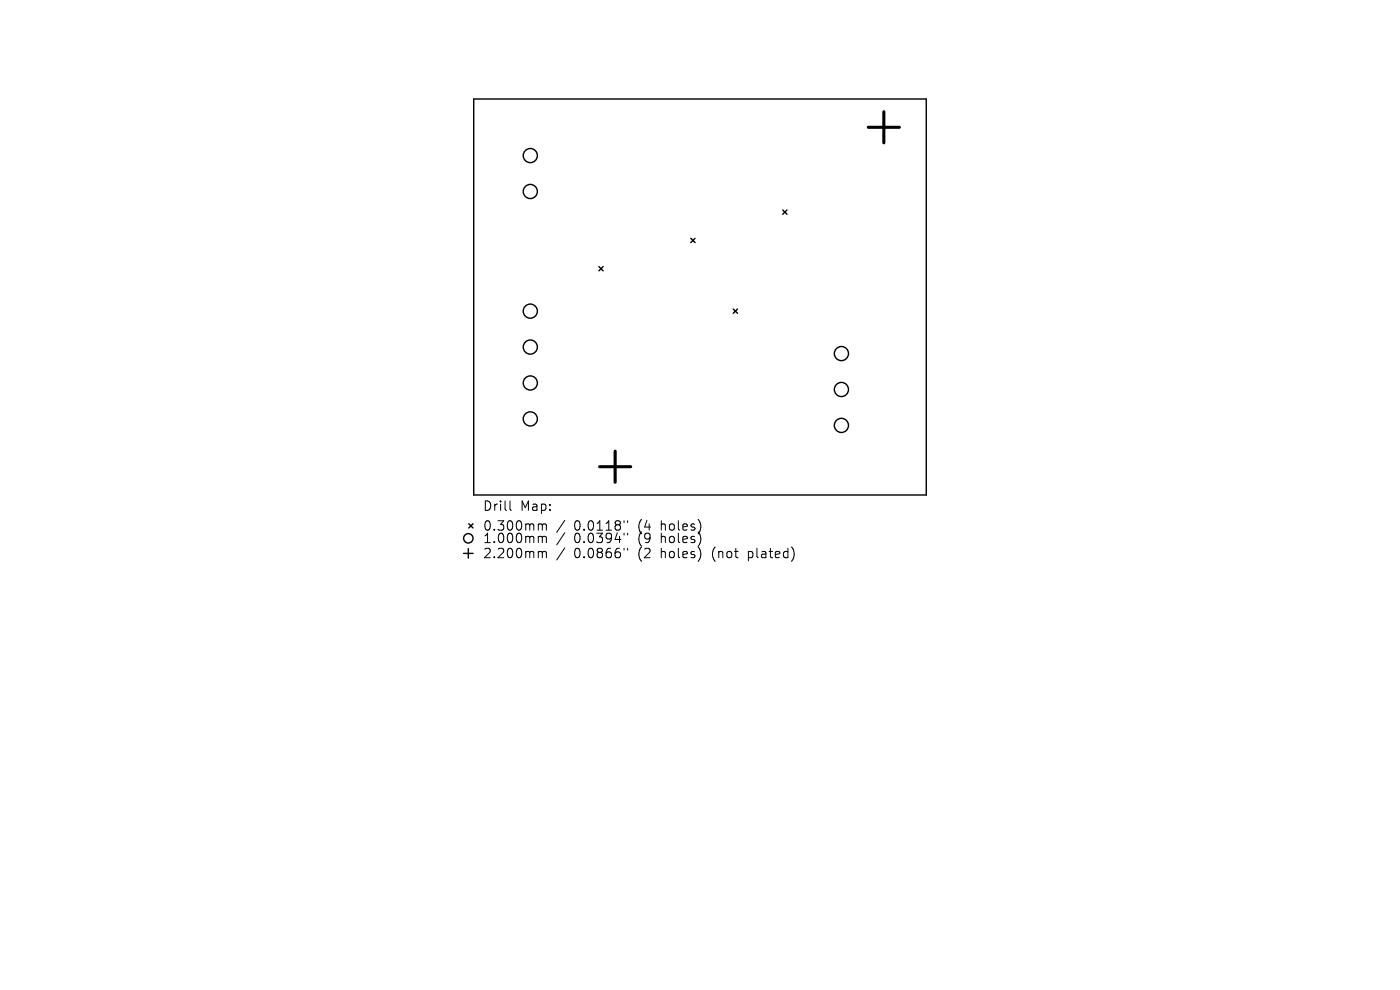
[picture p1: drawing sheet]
<svg xmlns="http://www.w3.org/2000/svg" width="297mm" height="210mm" viewBox="0 0 297 210" stroke-linecap="round" stroke-linejoin="round" font-family="sans-serif">
<defs><g id="words">
<g font-size="2.8">
<text x="102.4" y="108.7">Drill</text>
<text x="102.4" y="112.9">0.300mm</text>
<text x="110.4" y="108.7">Map:</text>
<text x="121.8" y="112.9">0.0118&quot;</text>
<text x="135.5" y="112.9">(4</text>
<text x="140.5" y="112.9">holes)</text>
<text x="102.4" y="115.5">1.000mm</text>
<text x="102.4" y="118.7">2.200mm</text>
<text x="121.8" y="115.5">0.0394&quot;</text>
<text x="121.8" y="118.7">0.0866&quot;</text>
<text x="135.5" y="115.5">(9</text>
<text x="135.5" y="118.7">(2</text>
<text x="140.5" y="115.5">holes)</text>
<text x="140.5" y="118.7">holes)</text>
<text x="151.5" y="118.7">(not</text>
<text x="159.4" y="118.7">plated)</text>
</g>
</g></defs>
<g fill="none" stroke="#000" stroke-width=".3">
<path d="M100.5 21h96v84h-96zM127.1 56.6l.9 .9M128 56.6l-.9 .9M146.6 50.6l.9 .9M147.5 50.6l-.9 .9M166.1 44.6l.9 .9M167 44.6l-.9 .9M155.6 65.6l.9 .9M156.5 65.6l-.9 .9M98.4 117.4h2M99.4 116.4v2M99.5 111.1l.9 .9"/>
<path d="M100.4 111.1l-.9 .9"/>
<circle cx="112.5" cy="33" r="1.5"/>
<circle cx="112.5" cy="40.6" r="1.5"/>
<circle cx="112.5" cy="73.6" r="1.5"/>
<circle cx="112.5" cy="66" r="1.5"/>
<circle cx="178.5" cy="75" r="1.5"/>
<circle cx="112.5" cy="81.2" r="1.5"/>
<circle cx="112.5" cy="88.9" r="1.5"/>
<circle cx="178.5" cy="90.2" r="1.5"/>
<circle cx="178.5" cy="82.6" r="1.5"/>
<circle cx="99.4" cy="114.2" r="1"/>
</g>
<path d="M184.2 27h6.6M187.5 23.7v6.6M127.2 99h6.6M130.5 95.7v6.6" fill="none" stroke="#000" stroke-width=".66"/>
<g fill="none" stroke="#000" stroke-width=".21">
<path d="M108.2 106.3v1.7l.3 .3M114.5 111.1l.5 .1 .1 .2M114.5 113.8l.5 .1 .1 .2M114.5 117l.5 .1 .1 .2M115.1 111.4l.2-.3 .5 .1 .1 1.3M115.1 111.4v1.1M115.1 114.1v1M115.1 117.3v1M115.1 114.1l.2-.3 .5 .1 .1 1.2M115.1 117.3l.2-.3 .5 .1 .1 1.2M119.8 110.4l-1.7 2.5M119.8 113l-1.7 2.6"/>
<path d="M119.8 116.2l-1.7 2.6M132.4 110.5v.3M132.4 113.1v.4M132.4 116.3v.4M133.1 110.5v.3M133.1 113.1v.4M133.1 116.3v.4"/>
</g>
<use href="#words"/>
</svg>
